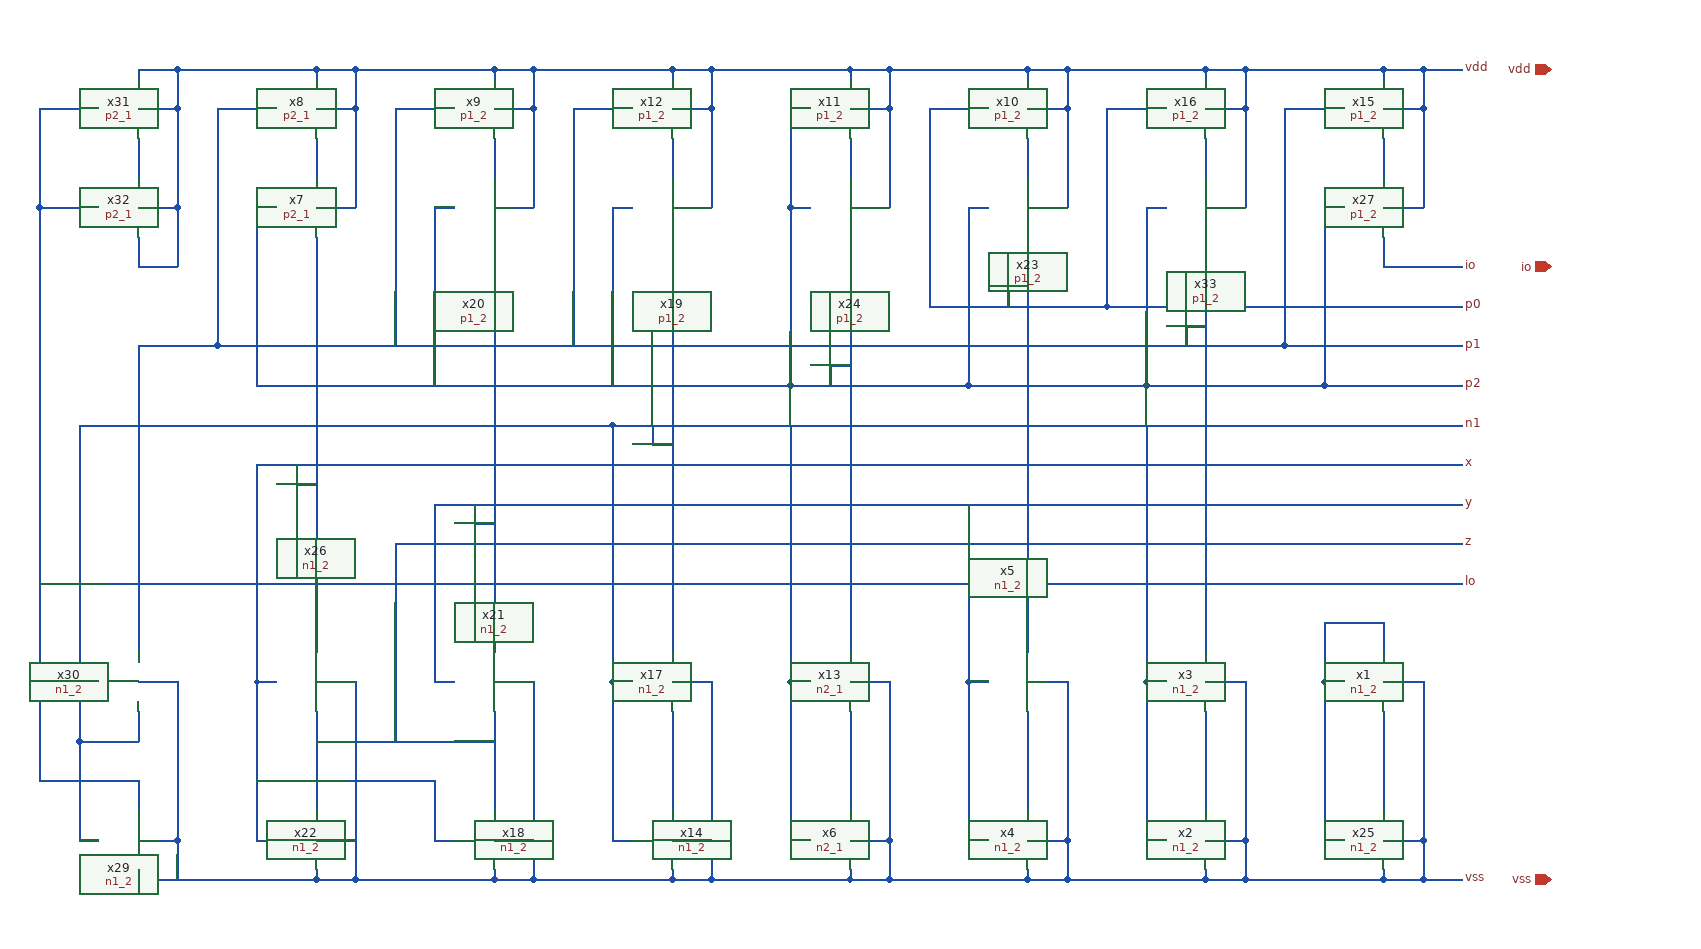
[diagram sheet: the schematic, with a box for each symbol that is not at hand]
v {xschem version=2.9.9 file_version=1.2 }
G {}
K {}
V {}
S {}
E {}
N 320 -210 320 -110 { lab=z}
N 260 -240 280 -240 { lab=x}
N 260 -240 260 -80 { lab=x}
N 260 -80 280 -80 { lab=x}
N 320 -240 360 -240 { lab=vss}
N 360 -240 360 -40 { lab=vss}
N 320 -40 360 -40 { lab=vss}
N 320 -50 320 -40 { lab=vss}
N 320 -80 360 -80 { lab=vss}
N 500 -210 500 -110 { lab=z}
N 440 -240 460 -240 { lab=y}
N 440 -80 460 -80 { lab=x}
N 500 -240 540 -240 { lab=vss}
N 540 -240 540 -40 { lab=vss}
N 500 -40 540 -40 { lab=vss}
N 500 -50 500 -40 { lab=vss}
N 500 -80 540 -80 { lab=vss}
N 440 -140 440 -80 { lab=x}
N 260 -140 440 -140 { lab=x}
N 320 -180 500 -180 { lab=z}
N 680 -210 680 -110 { lab=#net1}
N 620 -240 640 -240 { lab=n1}
N 620 -80 640 -80 { lab=x}
N 680 -240 720 -240 { lab=vss}
N 720 -240 720 -40 { lab=vss}
N 680 -40 720 -40 { lab=vss}
N 680 -50 680 -40 { lab=vss}
N 680 -80 720 -80 { lab=vss}
N 620 -140 620 -80 { lab=x}
N 500 -300 500 -270 { lab=y}
N 680 -300 680 -270 { lab=n1}
N 320 -300 320 -270 { lab=x}
N 320 -790 320 -750 { lab=#net2}
N 260 -720 280 -720 { lab=p2}
N 320 -820 360 -820 { lab=vdd}
N 320 -720 360 -720 { lab=vdd}
N 360 -820 360 -720 { lab=vdd}
N 360 -860 360 -820 { lab=vdd}
N 320 -860 360 -860 { lab=vdd}
N 320 -860 320 -850 { lab=vdd}
N 500 -790 500 -750 { lab=#net3}
N 440 -720 460 -720 { lab=p2}
N 500 -820 540 -820 { lab=vdd}
N 500 -720 540 -720 { lab=vdd}
N 540 -820 540 -720 { lab=vdd}
N 540 -860 540 -820 { lab=vdd}
N 500 -860 540 -860 { lab=vdd}
N 500 -860 500 -850 { lab=vdd}
N 320 -690 320 -300 { lab=x}
N 500 -690 500 -300 { lab=y}
N 680 -790 680 -750 { lab=#net4}
N 620 -720 640 -720 { lab=p2}
N 680 -820 720 -820 { lab=vdd}
N 680 -720 720 -720 { lab=vdd}
N 720 -820 720 -720 { lab=vdd}
N 720 -860 720 -820 { lab=vdd}
N 680 -860 720 -860 { lab=vdd}
N 680 -860 680 -850 { lab=vdd}
N 360 -860 500 -860 { lab=vdd}
N 540 -860 680 -860 { lab=vdd}
N 680 -690 680 -300 { lab=n1}
N 360 -40 500 -40 { lab=vss}
N 540 -40 680 -40 { lab=vss}
N 860 -210 860 -110 { lab=#net5}
N 800 -80 820 -80 { lab=n1}
N 800 -240 800 -80 { lab=n1}
N 800 -240 820 -240 { lab=n1}
N 860 -240 900 -240 { lab=vss}
N 900 -240 900 -80 { lab=vss}
N 860 -80 900 -80 { lab=vss}
N 900 -80 900 -40 { lab=vss}
N 860 -40 900 -40 { lab=vss}
N 860 -50 860 -40 { lab=vss}
N 860 -790 860 -750 { lab=#net6}
N 800 -820 820 -820 { lab=p2}
N 800 -720 820 -720 { lab=p2}
N 860 -820 900 -820 { lab=vdd}
N 900 -860 900 -820 { lab=vdd}
N 860 -860 900 -860 { lab=vdd}
N 860 -860 860 -850 { lab=vdd}
N 860 -720 900 -720 { lab=vdd}
N 900 -820 900 -720 { lab=vdd}
N 1040 -210 1040 -110 { lab=#net7}
N 980 -80 1000 -80 { lab=y}
N 980 -240 980 -80 { lab=y}
N 980 -240 1000 -240 { lab=y}
N 1040 -240 1080 -240 { lab=vss}
N 1080 -240 1080 -80 { lab=vss}
N 1040 -80 1080 -80 { lab=vss}
N 1080 -80 1080 -40 { lab=vss}
N 1040 -40 1080 -40 { lab=vss}
N 1040 -50 1040 -40 { lab=vss}
N 1040 -790 1040 -750 { lab=#net8}
N 980 -720 1000 -720 { lab=p2}
N 1040 -820 1080 -820 { lab=vdd}
N 1080 -860 1080 -820 { lab=vdd}
N 1040 -860 1080 -860 { lab=vdd}
N 1040 -860 1040 -850 { lab=vdd}
N 1040 -720 1080 -720 { lab=vdd}
N 1080 -820 1080 -720 { lab=vdd}
N 1220 -210 1220 -110 { lab=#net9}
N 1160 -80 1180 -80 { lab=n1}
N 1160 -240 1160 -80 { lab=n1}
N 1160 -240 1180 -240 { lab=n1}
N 1220 -240 1260 -240 { lab=vss}
N 1260 -240 1260 -80 { lab=vss}
N 1220 -80 1260 -80 { lab=vss}
N 1260 -80 1260 -40 { lab=vss}
N 1220 -40 1260 -40 { lab=vss}
N 1220 -50 1220 -40 { lab=vss}
N 1220 -790 1220 -750 { lab=#net10}
N 1160 -720 1180 -720 { lab=p2}
N 1220 -820 1260 -820 { lab=vdd}
N 1260 -860 1260 -820 { lab=vdd}
N 1220 -860 1260 -860 { lab=vdd}
N 1220 -860 1220 -850 { lab=vdd}
N 1220 -720 1260 -720 { lab=vdd}
N 1260 -820 1260 -720 { lab=vdd}
N 860 -690 860 -270 { lab=p2}
N 1040 -690 1040 -270 { lab=p0}
N 1220 -690 1220 -270 { lab=p1}
N 1400 -210 1400 -110 { lab=#net11}
N 1340 -80 1360 -80 { lab=#net12}
N 1340 -240 1340 -80 { lab=#net12}
N 1340 -240 1360 -240 { lab=#net12}
N 1400 -240 1440 -240 { lab=vss}
N 1440 -240 1440 -80 { lab=vss}
N 1400 -80 1440 -80 { lab=vss}
N 1440 -80 1440 -40 { lab=vss}
N 1400 -40 1440 -40 { lab=vss}
N 1400 -50 1400 -40 { lab=vss}
N 1400 -790 1400 -750 { lab=#net13}
N 1340 -720 1360 -720 { lab=p2}
N 1400 -820 1440 -820 { lab=vdd}
N 1440 -860 1440 -820 { lab=vdd}
N 1400 -860 1440 -860 { lab=vdd}
N 1400 -860 1400 -850 { lab=vdd}
N 1400 -720 1440 -720 { lab=vdd}
N 1440 -820 1440 -720 { lab=vdd}
N 1400 -300 1400 -270 { lab=#net12}
N 220 -820 280 -820 { lab=p1}
N 220 -820 220 -580 { lab=p1}
N 940 -820 1000 -820 { lab=p0}
N 940 -820 940 -620 { lab=p0}
N 1120 -820 1180 -820 { lab=p0}
N 940 -620 1120 -620 { lab=p0}
N 1120 -820 1120 -620 { lab=p0}
N 800 -720 800 -540 { lab=p2}
N 800 -540 980 -540 { lab=p2}
N 980 -720 980 -540 { lab=p2}
N 980 -540 1160 -540 { lab=p2}
N 1160 -720 1160 -540 { lab=p2}
N 1160 -540 1340 -540 { lab=p2}
N 1340 -720 1340 -540 { lab=p2}
N 1300 -820 1360 -820 { lab=p1}
N 1300 -820 1300 -580 { lab=p1}
N 220 -580 1300 -580 { lab=p1}
N 260 -720 260 -540 { lab=p2}
N 260 -540 800 -540 { lab=p2}
N 440 -720 440 -540 { lab=p2}
N 620 -720 620 -540 { lab=p2}
N 580 -820 640 -820 { lab=p1}
N 580 -820 580 -580 { lab=p1}
N 400 -820 460 -820 { lab=p1}
N 400 -820 400 -580 { lab=p1}
N 720 -860 860 -860 { lab=vdd}
N 900 -860 1040 -860 { lab=vdd}
N 1080 -860 1220 -860 { lab=vdd}
N 1260 -860 1400 -860 { lab=vdd}
N 1120 -620 1480 -620 { lab=p0}
N 1300 -580 1480 -580 { lab=p1}
N 1340 -540 1480 -540 { lab=p2}
N 140 -240 180 -240 { lab=vss}
N 180 -240 180 -80 { lab=vss}
N 140 -80 180 -80 { lab=vss}
N 140 -820 180 -820 { lab=vdd}
N 180 -860 180 -820 { lab=vdd}
N 180 -860 320 -860 { lab=vdd}
N 140 -860 180 -860 { lab=vdd}
N 140 -860 140 -850 { lab=vdd}
N 140 -790 140 -750 { lab=#net14}
N 180 -820 180 -720 { lab=vdd}
N 140 -720 180 -720 { lab=vdd}
N 140 -690 140 -660 { lab=vdd}
N 140 -660 180 -660 { lab=vdd}
N 180 -720 180 -660 { lab=vdd}
N 80 -720 100 -720 { lab=lo}
N 40 -820 40 -720 { lab=lo}
N 140 -140 140 -110 { lab=lo}
N 140 -210 140 -180 { lab=n1}
N 80 -180 80 -80 { lab=n1}
N 40 -240 40 -140 { lab=lo}
N 140 -580 220 -580 { lab=p1}
N 140 -580 140 -270 { lab=p1}
N 80 -80 100 -80 { lab=n1}
N 80 -180 140 -180 { lab=n1}
N 40 -140 140 -140 { lab=lo}
N 40 -240 100 -240 { lab=lo}
N 40 -720 40 -240 { lab=lo}
N 40 -720 80 -720 { lab=lo}
N 40 -820 100 -820 { lab=lo}
N 40 -340 1480 -340 { lab=lo}
N 140 -50 140 -40 { lab=vss}
N 140 -40 320 -40 { lab=vss}
N 180 -80 180 -40 { lab=vss}
N 400 -380 400 -180 { lab=z}
N 400 -380 1480 -380 { lab=z}
N 1340 -300 1400 -300 { lab=#net12}
N 1340 -300 1340 -240 { lab=#net12}
N 440 -420 440 -240 { lab=y}
N 260 -460 260 -240 { lab=x}
N 440 -420 1480 -420 { lab=y}
N 260 -460 1480 -460 { lab=x}
N 620 -500 620 -240 { lab=n1}
N 620 -500 1480 -500 { lab=n1}
N 300 -460 300 -440 { lab=x}
N 300 -440 320 -440 { lab=x}
N 480 -420 480 -400 { lab=y}
N 480 -400 500 -400 { lab=y}
N 660 -500 660 -480 { lab=n1}
N 660 -480 680 -480 { lab=n1}
N 720 -40 860 -40 { lab=vss}
N 900 -40 1040 -40 { lab=vss}
N 1080 -40 1220 -40 { lab=vss}
N 1260 -40 1400 -40 { lab=vss}
N 800 -500 800 -240 { lab=n1}
N 1400 -690 1400 -660 { lab=io}
N 1400 -660 1480 -660 { lab=io}
N 800 -820 800 -720 { lab=p2}
N 840 -560 840 -540 { lab=p2}
N 840 -560 860 -560 { lab=p2}
N 1200 -600 1220 -600 { lab=p1}
N 1200 -600 1200 -580 { lab=p1}
N 80 -500 80 -180 { lab=n1}
N 80 -500 620 -500 { lab=n1}
N 1440 -40 1480 -40 { lab=vss}
N 1440 -860 1480 -860 { lab=vdd}
N 1020 -640 1040 -640 { lab=p0}
N 1020 -640 1020 -620 { lab=p0}
N 620 -240 620 -140 {}
N 980 -420 980 -240 {}
N 1160 -500 1160 -240 {}
C {../ARRAY/p1_2.sym} 660 -820 0 0 {name=x12}
C {../ARRAY/n1_2.sym} 1380 -80 0 0 {name=x25}
C {../ARRAY/p2_1.sym} 120 -820 0 0 {name=x31}
C {devices/lab_pin.sym} 1480 -660 0 1 {name=l1 sig_type=std_logic lab=io}
C {devices/lab_pin.sym} 1480 -340 0 1 {name=l2 sig_type=std_logic lab=lo}
C {devices/lab_pin.sym} 1480 -620 0 1 {name=l3 sig_type=std_logic lab=p0}
C {devices/lab_pin.sym} 1480 -580 0 1 {name=l4 sig_type=std_logic lab=p1}
C {devices/lab_pin.sym} 1480 -540 0 1 {name=l5 sig_type=std_logic lab=p2}
C {devices/lab_pin.sym} 1480 -500 0 1 {name=l6 sig_type=std_logic lab=n1}
C {devices/lab_pin.sym} 1480 -460 0 1 {name=l7 sig_type=std_logic lab=x}
C {devices/lab_pin.sym} 1480 -420 0 1 {name=l8 sig_type=std_logic lab=y}
C {devices/lab_pin.sym} 1480 -380 0 1 {name=l9 sig_type=std_logic lab=z}
C {devices/lab_pin.sym} 1480 -860 0 1 {name=l10 sig_type=std_logic lab=vdd}
C {devices/lab_pin.sym} 1480 -40 0 1 {name=l11 sig_type=std_logic lab=vss}
C {devices/iopin.sym} 1570 -860 0 0 {name=p1 lab=vdd}
C {devices/iopin.sym} 1570 -40 0 0 {name=p2 lab=vss}
C {devices/iopin.sym} 1570 -660 0 0 {name=p3 lab=io}
C {../ARRAY/p2_1.sym} 120 -720 0 0 {name=x32}
C {../ARRAY/p2_1.sym} 300 -720 0 0 {name=x7}
C {../ARRAY/p2_1.sym} 300 -820 0 0 {name=x8}
C {../ARRAY/p1_2.sym} 480 -820 0 0 {name=x9}
C {../ARRAY/p1_2.sym} 1020 -820 0 0 {name=x10}
C {../ARRAY/p1_2.sym} 840 -820 0 0 {name=x11}
C {../ARRAY/p1_2.sym} 1380 -820 0 0 {name=x15}
C {../ARRAY/p1_2.sym} 1200 -820 0 0 {name=x16}
C {../ARRAY/p1_2.sym} 660 -720 0 0 {name=x19}
C {../ARRAY/p1_2.sym} 480 -720 0 0 {name=x20}
C {../ARRAY/p1_2.sym} 1020 -720 0 0 {name=x23}
C {../ARRAY/p1_2.sym} 840 -720 0 0 {name=x24}
C {../ARRAY/p1_2.sym} 1380 -720 0 0 {name=x27}
C {../ARRAY/p1_2.sym} 1200 -720 0 0 {name=x33}
C {../ARRAY/n1_2.sym} 1380 -240 0 0 {name=x1}
C {../ARRAY/n1_2.sym} 1200 -80 0 0 {name=x2}
C {../ARRAY/n1_2.sym} 1200 -240 0 0 {name=x3}
C {../ARRAY/n1_2.sym} 1020 -80 0 0 {name=x4}
C {../ARRAY/n1_2.sym} 1020 -240 0 0 {name=x5}
C {../ARRAY/n2_1.sym} 840 -80 0 0 {name=x6}
C {../ARRAY/n2_1.sym} 840 -240 0 0 {name=x13}
C {../ARRAY/n1_2.sym} 660 -80 0 0 {name=x14}
C {../ARRAY/n1_2.sym} 660 -240 0 0 {name=x17}
C {../ARRAY/n1_2.sym} 480 -80 0 0 {name=x18}
C {../ARRAY/n1_2.sym} 480 -240 0 0 {name=x21}
C {../ARRAY/n1_2.sym} 300 -80 0 0 {name=x22}
C {../ARRAY/n1_2.sym} 300 -240 0 0 {name=x26}
C {../ARRAY/n1_2.sym} 120 -80 0 0 {name=x29}
C {../ARRAY/n1_2.sym} 120 -240 0 0 {name=x30}
